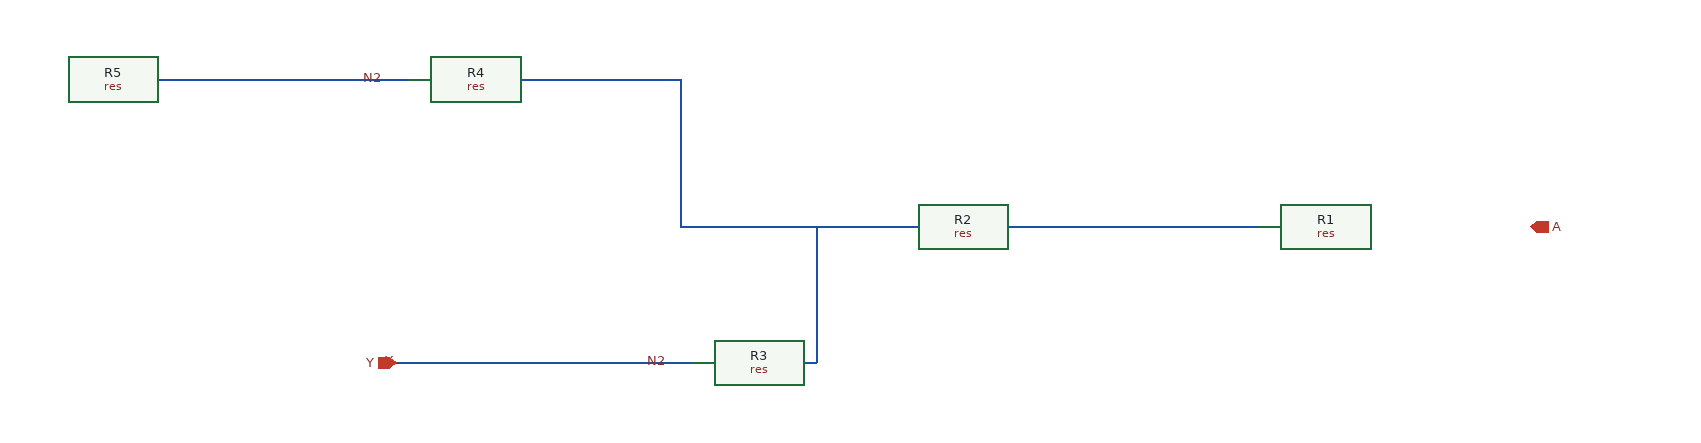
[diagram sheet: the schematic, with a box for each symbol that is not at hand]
v {xschem version=2.9.7 file_version=1.1}
G {}
V {}
S {}
E {}
N 740 380 1010 380 {lab=N1}
C {devices/lab_wire.sym} 740 380 0 0 {lab=N1}
N 490 500 620 500 {lab=N2}
N 620 500 620 380 {lab=N2}
N 620 380 760 380 {lab=N2}
C {devices/lab_wire.sym} 490 500 0 0 {lab=N2}
N 240 250 500 250 {lab=N2}
N 500 250 500 380 {lab=N2}
N 500 380 760 380 {lab=N2}
C {devices/lab_wire.sym} 240 250 0 0 {lab=N2}
N 250 500 510 500 {lab=Y}
C {devices/lab_wire.sym} 250 500 0 0 {lab=Y}
N -10 250 260 250 {lab=N3}
C {devices/lab_wire.sym} -10 250 0 0 {lab=N3}
C {devices/res.sym} 1000 380 0 0 {name=R1 value=1k}
C {devices/res.sym} 750 380 0 0 {name=R2 value=2k}
C {devices/res.sym} 500 500 0 0 {name=R3 value=3k}
C {devices/res.sym} 250 250 0 0 {name=R4 value=4k}
C {devices/res.sym} 0 250 0 0 {name=R5 value=5k}
C {devices/opin.sym} 1250 380 0 0 {lab=A}
C {devices/ipin.sym} 250 500 0 0 {lab=Y}
